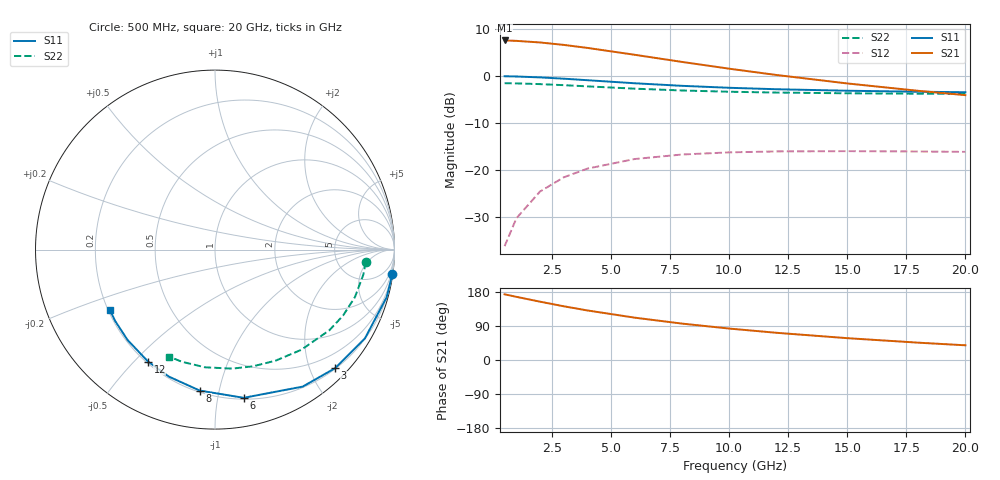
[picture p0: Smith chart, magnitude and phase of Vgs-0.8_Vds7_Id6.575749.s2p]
# Hz S RI R 50
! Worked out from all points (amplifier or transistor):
!   12 points, 500 MHz to 20 GHz, reference 50 ohm
!   highest |S21| = 7.6 dB at 500 MHz (marker M1)
!   |S21| within 3 dB of that: start of sweep to 5.946 GHz
!   unconditionally stable (mu >= 1): 14.96 GHz to end of sweep
!   at 2 GHz: K = 0.11, MSG = 15.8 dB, |S12| = -24.5 dB
!   at 8 GHz: K = 0.47, MSG = 9.8 dB, |S12| = -16.6 dB
!   at 20 GHz: K = 1.46, MAG = 2.0 dB, |S12| = -16.1 dB
!   S11 on the Smith chart (normalised r, x): 500 MHz: 0, -15; 3 GHz: 0.21, -2.42; 6 GHz: 0.21, -1.19; 8 GHz: 0.21, -0.87; 12 GHz: 0.21, -0.55; 20 GHz: 0.21, -0.25
5e8  0.9887 -0.1359  -2.378 0.2788  0.0015 0.0156  0.8395 -0.0701
1e9  0.9557 -0.2665  -2.307 0.5457  0.00588 0.0305  0.8268 -0.1384
2e9  0.8356 -0.4941  -2.047 1.005  0.0217 0.0555  0.7802 -0.2636
3e9  0.6696 -0.6603  -1.69 1.328  0.0434 0.0722  0.7136 -0.3676
4e9  0.4886 -0.7634  -1.305 1.511  0.0666 0.0803  0.637 -0.4495
6e9  0.1597 -0.8259  -0.6259 1.567  0.1068 0.0774  0.4813 -0.558
8e9  -0.0855 -0.7853  -0.1506 1.41  0.1337 0.0619  0.3382 -0.6186
1e10  -0.2557 -0.7082  0.1462 1.192  0.1491 0.0433  0.2106 -0.6504
1.2e10  -0.3732 -0.6236  0.3214 0.9782  0.1568 0.0257  0.096 -0.663
1.5e10  -0.4873 -0.5034  0.4483 0.707  0.1599 0.00351  -0.0551 -0.6558
1.8e10  -0.5565 -0.3972  0.4881 0.5011  0.158 -0.0135  -0.1829 -0.6255
2e10  -0.587 -0.3338  0.4901 0.3943  0.1556 -0.0226  -0.2561 -0.5962
